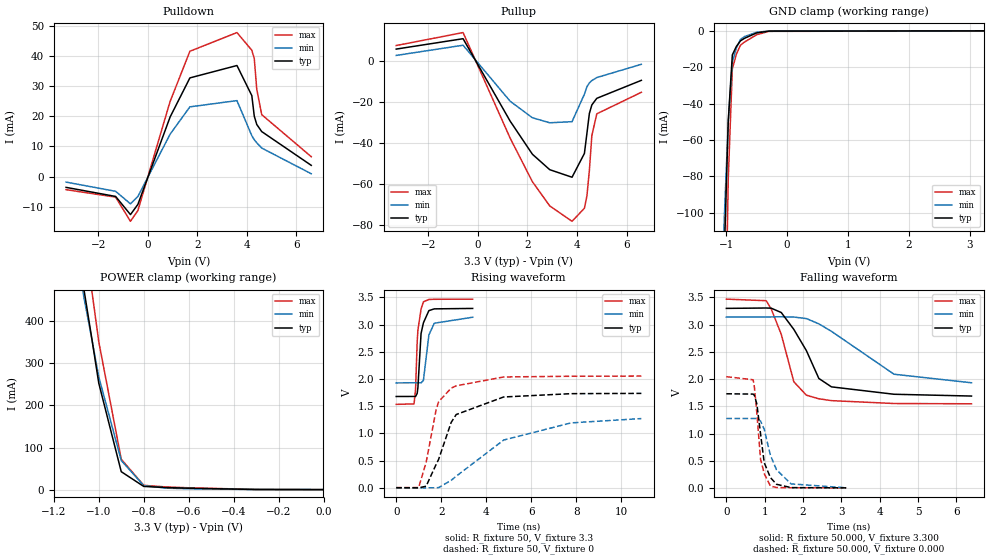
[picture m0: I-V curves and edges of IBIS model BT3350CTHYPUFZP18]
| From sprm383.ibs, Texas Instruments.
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|   Model Cell BT3350CTHYPUFZP18
[Model]   BT3350CTHYPUFZP18
Model_type   I/O
Polarity   Non-Inverting
Enable   Active-Low
Vinl =  0.8V
Vinh =  2V
Cref =  15.0000pF
Rref =  100.0000M
Vref =  0V
Vmeas =  1.65
C_comp   1.502503p   1.466075p   1.538374p
[Model Spec]
Vinl   0.8V   0.8V   0.8V
Vinh   2V   2V   2V
[Temperature Range]   25   105   0
[Voltage Range]   3.3   3.14   3.47
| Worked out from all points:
|   slope of the pulldown table from 0 to 0.495 V, typ, clamps not added: 44 ohm
|   slope of the pullup table from 0 to 0.495 V, typ, clamps not added: 42.8 ohm
|   GND clamp passes 1 mA (typ) near -0.48 V on its own axis
|   POWER clamp passes 1 mA (typ) near -0.41 V on its own axis
|   rising waveform, R_fixture 50, V_fixture 3.3: 20-80 % time 190ps typ, 246ps min, 155ps max; typ from 1.68 V to 3.3 V
|   rising waveform, R_fixture 50, V_fixture 0: 20-80 % time 1.09ns typ, 3.19ns min, 654ps max; typ from 0.003 V to 1.74 V
|   falling waveform, R_fixture 50.000, V_fixture 3.300: 20-80 % time 714ps typ, 1.44ns min, 481ps max; typ from 3.3 V to 1.69 V
|   falling waveform, R_fixture 50.000, V_fixture 0.000: 20-80 % time 214ps typ, 398ps min, 167ps max; typ from 1.73 V to 0.004 V
[POWER_clamp]
|   voltage   I(typ)   I(min)   I(max)
-3.3V     9.961A     8.611A     10.94A
-1.067V   478.9mA    459.3mA    610.8mA
-1.033V   365.9mA    363.6mA    481.1mA
-1V       253mA      268mA      351.4mA
-900mV    42.61mA    69.09mA    72.29mA
-800mV    7.588mA    9.637mA    10.15mA
-700mV    4.837mA    3.413mA    6.304mA
-600mV    3.264mA    2.054mA    4.281mA
-300mV    294.4uA    124uA      421.6uA
-11.55fV  111.7nA    122.5nA    531.5nA
[Pulldown]
|   voltage   I(typ)   I(min)   I(max)
-3.3V     -3.556mA   -1.81mA    -4.313mA
-1.3V     -6.559mA   -4.855mA   -6.788mA
-700mV    -12.57mA   -9.011mA   -14.79mA
-400mV    -9.189mA   -6.568mA   -11.22mA
900mV     19.73mA    14.05mA    24.87mA
1.7V      32.7mA     23.11mA    41.52mA
3.6V      36.8mA     25.18mA    47.71mA
4.2V      26.84mA    13.56mA    41.86mA
4.3V      20mA       12.22mA    39.07mA
4.4V      17.27mA    11.2mA     28.91mA
4.6V      14.92mA    9.466mA    20.53mA
6.6V      3.738mA    957.8uA    6.603mA
[Pullup]
|   voltage   I(typ)   I(min)   I(max)
-3.3V     6.065mA    2.956mA    7.802mA
-600mV    11.14mA    7.957mA    14.14mA
1.3V      -29.12mA   -19.41mA   -37.44mA
2.2V      -45.34mA   -27.51mA   -58.77mA
2.9V      -52.89mA   -29.96mA   -70.6mA
3.8V      -56.58mA   -29.42mA   -78.12mA
4.3V      -44.95mA   -15.98mA   -71.73mA
4.4V      -35.27mA   -12.36mA   -65.78mA
4.5V      -25.42mA   -10.48mA   -53.4mA
4.6V      -21.24mA   -9.347mA   -36.22mA
4.8V      -18mA      -7.852mA   -25.58mA
6.6V      -9.208mA   -1.37mA    -15.06mA
[GND_clamp]
|   voltage   I(typ)   I(min)   I(max)
-3.3V     -13.48A    -11.6A     -14.64A
-1.1V     -237.5mA   -179.6mA   -391mA
-1.033V   -124.2mA   -103.9mA   -204.6mA
-966.7mV  -49.5mA    -49.77mA   -81.23mA
-900mV    -13.27mA   -17.19mA   -20.98mA
-833.3mV  -8.566mA   -9.427mA   -12.84mA
-766.7mV  -5.513mA   -4.752mA   -7.902mA
-700mV    -4.108mA   -3.166mA   -6.147mA
-500mV    -1.143mA   -794.1uA   -2.132mA
-300mV    -166.2uA   -102.4uA   -290.4uA
3.233V    -8.734uA   9.395uA    -38.37uA
[Ramp]
| variable   typ   min   max
dV/dt_f   1.0019/0.7191069n  0.7872459/1.623878n   1.179669/0.4820844n
dV/dt_r   1.047343/1.100085n   0.7866504/3.393366n   1.235207/0.6500529n
R_load = 50
[Rising Waveform]
R_fixture = 50
V_fixture = 3.3
V_fixture_min = 3.14
V_fixture_max = 3.47
|   time   V(typ)   V(min)   V(max)
0s        1.68V      1.93V      1.535V
792ps     1.681V     1.931V     1.544V
860ps     1.681V     1.932V     1.813V
932ps     1.737V     1.931V     2.687V
964ps     1.844V     1.931V     2.9V
1.104ns   2.837V     1.931V     3.288V
1.208ns   3.034V     1.975V     3.421V
1.452ns   3.259V     2.812V     3.464V
1.692ns   3.291V     3.027V     3.467V
3.396ns   3.299V     3.137V     3.47V
[Rising Waveform]
R_fixture = 50
V_fixture = 0
V_fixture_min = 0
V_fixture_max = 0
|   time   V(typ)   V(min)   V(max)
0s        3.146mV    1.93mV     3.847mV
996ps     791.2uV    1.936mV    5.111mV
1.328ns   29.71mV    101.9uV    465.4mV
1.772ns   430.3mV    2.378mV    1.436V
1.884ns   524mV      4.058mV    1.584V
2.44ns    1.202V     138.2mV    1.833V
2.664ns   1.348V     213.8mV    1.876V
4.772ns   1.671V     879mV      2.039V
7.772ns   1.732V     1.195V     2.052V
10.89ns   1.737V     1.274V     2.055V
[Falling Waveform]
R_fixture = 50.000
V_fixture = 3.300
V_fixture_min = 3.140
V_fixture_max = 3.470
|  time   V(typ)   V(min)   V(max)
0s        3.3V       3.14V      3.47V
1.04ns    3.307V     3.143V     3.441V
1.172ns   3.303V     3.144V     3.286V
1.432ns   3.224V     3.145V     2.824V
1.76ns    2.914V     3.141V     1.952V
2.088ns   2.523V     3.113V     1.706V
2.412ns   2.013V     3.016V     1.64V
2.74ns    1.859V     2.879V     1.606V
4.372ns   1.723V     2.091V     1.553V
6.392ns   1.69V      1.934V     1.548V
[Falling Waveform]
R_fixture = 50.000
V_fixture = 0.000
V_fixture_min = 0.000
V_fixture_max = 0.000
|  time   V(typ)   V(min)   V(max)
0s        1.732V     1.278V     2.046V
700ps     1.726V     1.278V     1.989V
732ps     1.703V     1.279V     1.852V
796ps     1.544V     1.275V     1.377V
892ps     997.5mV    1.232V     530.4mV
988ps     467mV      1.079V     267.7mV
1.148ns   194.5mV    605.4mV    37.49mV
1.308ns   69.72mV    336.6mV    9.931mV
1.688ns   8.542mV    76.79mV    5.993mV
3.128ns   4.413mV    5.077mV    4.102mV
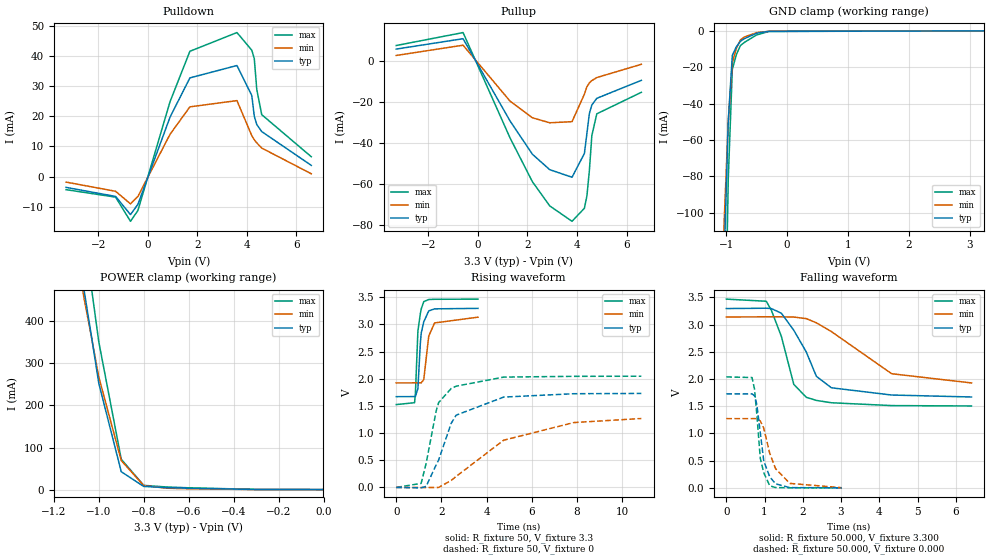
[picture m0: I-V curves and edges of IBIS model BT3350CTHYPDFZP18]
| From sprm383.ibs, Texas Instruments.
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|   Model Cell BT3350CTHYPDFZP18
[Model]   BT3350CTHYPDFZP18
Model_type   I/O
Polarity   Non-Inverting
Enable   Active-Low
Vinl =  0.8V
Vinh =  2V
Cref =  15.0000pF
Rref =  100.0000M
Vref =  0V
Vmeas =  1.65
C_comp   1.508835p   1.472578p   1.545342p
[Model Spec]
Vinl   0.8V   0.8V   0.8V
Vinh   2V   2V   2V
[Temperature Range]   25   105   0
[Voltage Range]   3.3   3.14   3.47
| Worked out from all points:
|   slope of the pulldown table from 0 to 0.495 V, typ, clamps not added: 44 ohm
|   slope of the pullup table from 0 to 0.495 V, typ, clamps not added: 42.8 ohm
|   GND clamp passes 1 mA (typ) near -0.49 V on its own axis
|   POWER clamp passes 1 mA (typ) near -0.40 V on its own axis
|   rising waveform, R_fixture 50, V_fixture 3.3: 20-80 % time 190ps typ, 246ps min, 157ps max; typ from 1.67 V to 3.3 V
|   rising waveform, R_fixture 50, V_fixture 0: 20-80 % time 1.09ns typ, 3.19ns min, 655ps max; typ from 0 V to 1.73 V
|   falling waveform, R_fixture 50.000, V_fixture 3.300: 20-80 % time 715ps typ, 1.44ns min, 479ps max; typ from 3.29 V to 1.67 V
|   falling waveform, R_fixture 50.000, V_fixture 0.000: 20-80 % time 213ps typ, 396ps min, 166ps max; typ from 1.73 V to 0.001 V
[POWER_clamp]
|   voltage   I(typ)   I(min)   I(max)
-3.3V     9.96A      8.611A     10.94A
-1.067V   478.9mA    459.2mA    610.8mA
-1.033V   365.9mA    363.6mA    481.1mA
-1V       253mA      268mA      351.4mA
-900mV    42.61mA    69.08mA    72.31mA
-800mV    7.612mA    9.647mA    10.2mA
-700mV    4.877mA    3.434mA    6.369mA
-600mV    3.319mA    2.085mA    4.366mA
-300mV    394.6uA    184.3uA    564.2uA
-11.55fV  142.7uA    86.75uA    197.1uA
[Pulldown]
|   voltage   I(typ)   I(min)   I(max)
-3.3V     -3.556mA   -1.81mA    -4.313mA
-1.3V     -6.558mA   -4.855mA   -6.788mA
-700mV    -12.57mA   -9.011mA   -14.79mA
-400mV    -9.189mA   -6.568mA   -11.22mA
900mV     19.74mA    14.05mA    24.87mA
1.7V      32.7mA     23.11mA    41.52mA
3.6V      36.8mA     25.18mA    47.71mA
4.2V      26.85mA    13.56mA    41.86mA
4.3V      20mA       12.22mA    39.07mA
4.4V      17.27mA    11.2mA     28.91mA
4.6V      14.92mA    9.466mA    20.53mA
6.6V      3.738mA    957.8uA    6.603mA
[Pullup]
|   voltage   I(typ)   I(min)   I(max)
-3.3V     6.065mA    2.955mA    7.802mA
-600mV    11.14mA    7.957mA    14.14mA
1.3V      -29.12mA   -19.41mA   -37.44mA
2.2V      -45.34mA   -27.51mA   -58.77mA
2.9V      -52.89mA   -29.96mA   -70.6mA
3.8V      -56.58mA   -29.42mA   -78.12mA
4.3V      -44.94mA   -15.98mA   -71.73mA
4.4V      -35.27mA   -12.36mA   -65.78mA
4.5V      -25.42mA   -10.48mA   -53.4mA
4.6V      -21.24mA   -9.347mA   -36.22mA
4.8V      -18mA      -7.852mA   -25.58mA
6.6V      -9.208mA   -1.37mA    -15.06mA
[GND_clamp]
|   voltage   I(typ)   I(min)   I(max)
-3.3V     -13.48A    -11.6A     -14.64A
-1.1V     -237.6mA   -179.7mA   -391.1mA
-1.033V   -124.3mA   -104mA     -204.6mA
-966.7mV  -49.55mA   -49.84mA   -81.29mA
-900mV    -13.32mA   -17.24mA   -21.02mA
-833.3mV  -8.603mA   -9.47mA    -12.87mA
-766.7mV  -5.537mA   -4.785mA   -7.915mA
-700mV    -4.118mA   -3.189mA   -6.143mA
-500mV    -1.111mA   -790.4uA   -2.074mA
-300mV    -91.74uA   -71.4uA    -180uA
3.233V    142.6uA    88.12uA    196.8uA
[Ramp]
| variable   typ   min   max
dV/dt_f   1.003801/0.7179774n  0.7885552/1.618059n   1.182195/0.4805983n
dV/dt_r   1.046072/1.105976n   0.785264/3.40284n   1.233956/0.6529987n
R_load = 50
[Rising Waveform]
R_fixture = 50
V_fixture = 3.3
V_fixture_min = 3.14
V_fixture_max = 3.47
|   time   V(typ)   V(min)   V(max)
0s        1.671V     1.924V     1.525V
812ps     1.672V     1.925V     1.56V
848ps     1.672V     1.925V     1.711V
960ps     1.819V     1.925V     2.878V
1.068ns   2.655V     1.925V     3.199V
1.108ns   2.843V     1.925V     3.286V
1.22ns    3.048V     1.987V     3.42V
1.44ns    3.249V     2.787V     3.459V
1.7ns     3.287V     3.028V     3.463V
3.62ns    3.296V     3.134V     3.466V
[Rising Waveform]
R_fixture = 50
V_fixture = 0
V_fixture_min = 0
V_fixture_max = 0
|   time   V(typ)   V(min)   V(max)
0s        47.1uV     22.63uV    79.1uV
1.104ns   -7.673mV   -136.5uV   74.88mV
1.324ns   19.79mV    -1.892mV   440.9mV
1.768ns   414.1mV    -1.08mV    1.408V
1.88ns    507.2mV    495.8uV    1.563V
2.432ns   1.179V     128.3mV    1.821V
2.652ns   1.33V      203.1mV    1.864V
4.756ns   1.663V     869.8mV    2.031V
7.856ns   1.725V     1.194V     2.045V
10.85ns   1.73V      1.269V     2.047V
[Falling Waveform]
R_fixture = 50.000
V_fixture = 3.300
V_fixture_min = 3.140
V_fixture_max = 3.470
|  time   V(typ)   V(min)   V(max)
0s        3.293V     3.138V     3.466V
1.044ns   3.299V     3.141V     3.427V
1.176ns   3.293V     3.142V     3.265V
1.44ns    3.207V     3.141V     2.78V
1.764ns   2.895V     3.137V     1.901V
2.092ns   2.494V     3.108V     1.663V
2.356ns   2.048V     3.031V     1.606V
2.748ns   1.838V     2.87V      1.563V
4.324ns   1.705V     2.096V     1.511V
6.412ns   1.669V     1.927V     1.504V
[Falling Waveform]
R_fixture = 50.000
V_fixture = 0.000
V_fixture_min = 0.000
V_fixture_max = 0.000
|  time   V(typ)   V(min)   V(max)
0s        1.725V     1.272V     2.038V
672ps     1.725V     1.272V     2.026V
736ps     1.692V     1.273V     1.818V
796ps     1.537V     1.269V     1.365V
888ps     1.014V     1.229V     542mV
980ps     490.5mV    1.093V     276.1mV
1.136ns   201.5mV    633.4mV    37.9mV
1.288ns   73.74mV    352mV      5.886mV
1.66ns    5.031mV    82.12mV    1.896mV
3.02ns    1.192mV    3.17mV     242uV
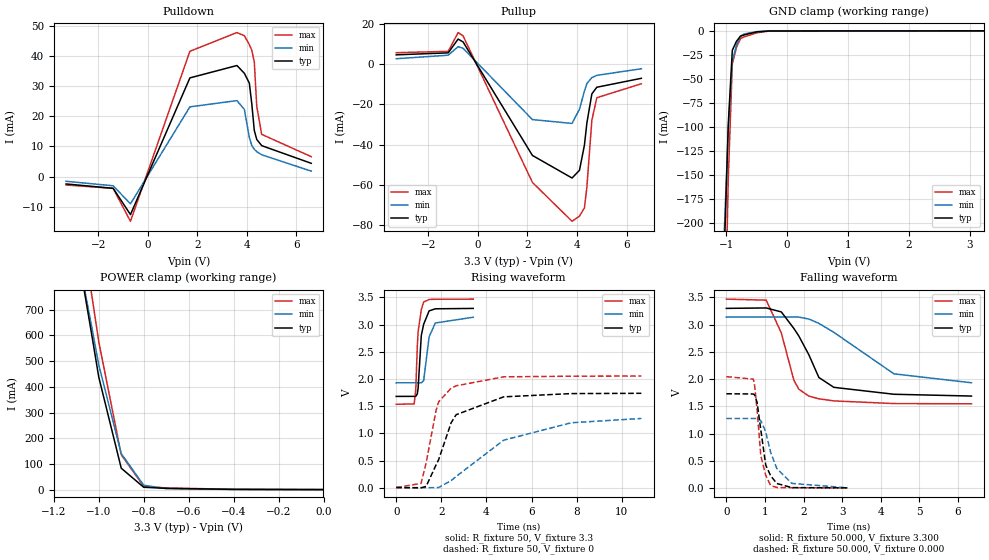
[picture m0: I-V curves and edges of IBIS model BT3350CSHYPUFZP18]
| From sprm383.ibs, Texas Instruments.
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|   Model Cell BT3350CSHYPUFZP18
[Model]   BT3350CSHYPUFZP18
Model_type   I/O
Polarity   Non-Inverting
Enable   Active-Low
Vinl =  0.8V
Vinh =  2V
Cref =  15.0000pF
Rref =  100.0000M
Vref =  0V
Vmeas =  1.65
C_comp   1.729411p   1.683527p   1.771376p
[Model Spec]
Vinl   0.8V   0.8V   0.8V
Vinh   2V   2V   2V
[Temperature Range]   25   105   0
[Voltage Range]   3.3   3.14   3.47
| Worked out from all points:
|   slope of the pulldown table from 0 to 0.495 V, typ, clamps not added: 44 ohm
|   slope of the pullup table from 0 to 0.495 V, typ, clamps not added: 42.8 ohm
|   GND clamp passes 1 mA (typ) near -0.48 V on its own axis
|   POWER clamp passes 1 mA (typ) near -0.41 V on its own axis
|   rising waveform, R_fixture 50, V_fixture 3.3: 20-80 % time 200ps typ, 262ps min, 161ps max; typ from 1.68 V to 3.3 V
|   rising waveform, R_fixture 50, V_fixture 0: 20-80 % time 1.08ns typ, 3.18ns min, 648ps max; typ from 0.003 V to 1.74 V
|   falling waveform, R_fixture 50.000, V_fixture 3.300: 20-80 % time 713ps typ, 1.43ns min, 481ps max; typ from 3.3 V to 1.69 V
|   falling waveform, R_fixture 50.000, V_fixture 0.000: 20-80 % time 225ps typ, 409ps min, 176ps max; typ from 1.73 V to 0.004 V
[POWER_clamp]
|   voltage   I(typ)   I(min)   I(max)
-3.3V     15.06A     13.76A     16A
-1.067V   785.8mA    796.7mA    959.4mA
-1.033V   611.7mA    640.9mA    767.4mA
-1V       437.6mA    485.2mA    575.3mA
-900mV    83.18mA    139.9mA    135.6mA
-800mV    9.15mA     17.08mA    12.66mA
-700mV    4.874mA    3.821mA    6.346mA
-400mV    906.7uA    477.6uA    1.218mA
-11.55fV  111.7nA    122.5nA    531.5nA
[Pulldown]
|   voltage   I(typ)   I(min)   I(max)
-3.3V     -2.42mA    -1.536mA   -2.768mA
-1.4V     -3.865mA   -3.029mA   -3.892mA
-700mV    -12.57mA   -9.01mA    -14.79mA
1.7V      32.7mA     23.11mA    41.52mA
3.6V      36.8mA     25.18mA    47.71mA
3.9V      34.21mA    22.24mA    46.65mA
4.1V      30.98mA    12.94mA    43.72mA
4.2V      24.06mA    10.3mA     41.84mA
4.3V      15.3mA     9.054mA    37.97mA
4.4V      12.31mA    8.283mA    23.22mA
4.6V      10.26mA    7.233mA    13.99mA
6.6V      4.412mA    1.834mA    6.626mA
[Pullup]
|   voltage   I(typ)   I(min)   I(max)
-3.3V     4.71mA     2.781mA    5.78mA
-1.2V     5.694mA    4.518mA    6.444mA
-800mV    12.56mA    8.755mA    15.79mA
-600mV    11.14mA    7.956mA    14.14mA
2.2V      -45.34mA   -27.51mA   -58.77mA
3.8V      -56.58mA   -29.42mA   -78.12mA
4.1V      -52.77mA   -22.36mA   -75.56mA
4.3V      -40.26mA   -13.34mA   -71.48mA
4.4V      -29.2mA    -9.578mA   -61.01mA
4.6V      -14.75mA   -6.625mA   -27.92mA
4.8V      -11.42mA   -5.502mA   -16.63mA
6.6V      -6.965mA   -2.214mA   -9.682mA
[GND_clamp]
|   voltage   I(typ)   I(min)   I(max)
-3.3V     -17.3A     -15.81A    -18.25A
-1.033V   -232.2mA   -209.7mA   -349.9mA
-966.7mV  -97.18mA   -102.7mA   -153.5mA
-900mV    -20.22mA   -31.77mA   -34.2mA
-833.3mV  -11mA      -14.95mA   -17.44mA
-766.7mV  -5.636mA   -5.437mA   -8.094mA
-700mV    -4.112mA   -3.216mA   -6.152mA
-500mV    -1.143mA   -794.3uA   -2.132mA
-300mV    -166.2uA   -102.4uA   -290.4uA
3.233V    -8.734uA   9.395uA    -38.37uA
[Ramp]
| variable   typ   min   max
dV/dt_f   1.001695/0.7159292n  0.7872142/1.616947n   1.179413/0.4810026n
dV/dt_r   1.04705/1.096909n   0.7864588/3.38681n   1.234969/0.6440918n
R_load = 50
[Rising Waveform]
R_fixture = 50
V_fixture = 3.3
V_fixture_min = 3.14
V_fixture_max = 3.47
|   time   V(typ)   V(min)   V(max)
0s        1.68V      1.93V      1.535V
796ps     1.681V     1.931V     1.542V
868ps     1.681V     1.931V     1.81V
936ps     1.727V     1.931V     2.605V
972ps     1.833V     1.931V     2.872V
1.112ns   2.799V     1.931V     3.275V
1.216ns   3.006V     1.97V      3.416V
1.46ns    3.254V     2.778V     3.464V
1.736ns   3.292V     3.031V     3.468V
3.416ns   3.299V     3.137V     3.47V
[Rising Waveform]
R_fixture = 50
V_fixture = 0
V_fixture_min = 0
V_fixture_max = 0
|   time   V(typ)   V(min)   V(max)
0s        3.146mV    1.93mV     3.847mV
1.104ns   -2.651mV   1.865mV    79.58mV
1.328ns   25.43mV    325.6uV    458.2mV
1.772ns   424.3mV    1.967mV    1.431V
1.88ns    514.8mV    3.472mV    1.58V
2.436ns   1.195V     131.1mV    1.832V
2.656ns   1.343V     206.5mV    1.875V
4.764ns   1.672V     874.6mV    2.04V
7.756ns   1.732V     1.195V     2.052V
10.87ns   1.737V     1.274V     2.055V
[Falling Waveform]
R_fixture = 50.000
V_fixture = 3.300
V_fixture_min = 3.140
V_fixture_max = 3.470
|  time   V(typ)   V(min)   V(max)
0s        3.3V       3.14V      3.47V
1.032ns   3.308V     3.143V     3.451V
1.424ns   3.235V     3.144V     2.849V
1.748ns   2.932V     3.142V     1.982V
1.876ns   2.794V     3.14V      1.817V
2.136ns   2.449V     3.104V     1.689V
2.396ns   2.031V     3.025V     1.64V
2.784ns   1.85V      2.86V      1.601V
4.34ns    1.723V     2.098V     1.552V
6.348ns   1.69V      1.934V     1.548V
[Falling Waveform]
R_fixture = 50.000
V_fixture = 0.000
V_fixture_min = 0.000
V_fixture_max = 0.000
|  time   V(typ)   V(min)   V(max)
0s        1.732V     1.278V     2.046V
700ps     1.728V     1.278V     2.001V
732ps     1.71V      1.278V     1.886V
796ps     1.577V     1.276V     1.442V
892ps     1.071V     1.241V     598.8mV
1.02ns    423.2mV    1.031V     235.5mV
1.148ns   225.4mV    654.8mV    47.46mV
1.308ns   84.09mV    359.6mV    10.27mV
1.696ns   8.561mV    86.11mV    5.947mV
3.136ns   4.391mV    5.082mV    4.064mV
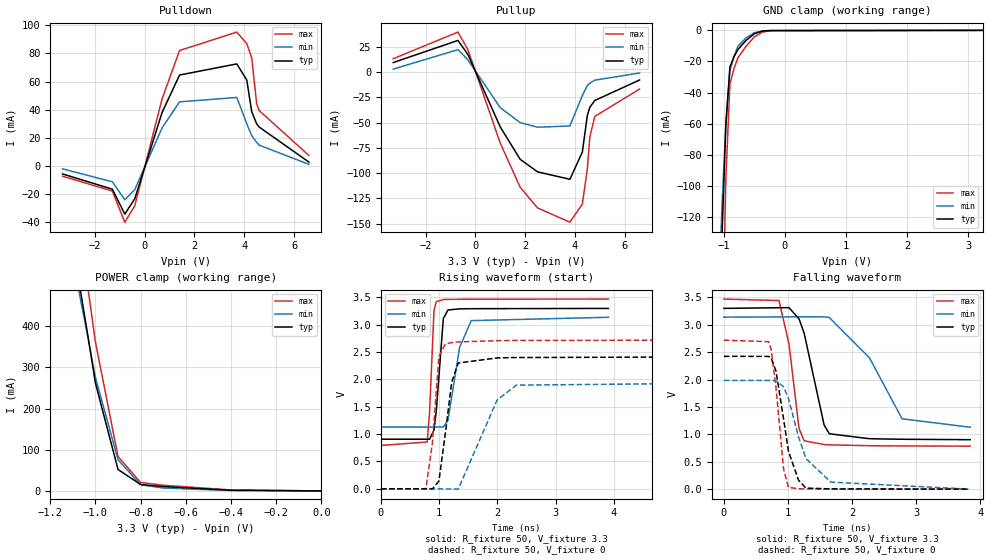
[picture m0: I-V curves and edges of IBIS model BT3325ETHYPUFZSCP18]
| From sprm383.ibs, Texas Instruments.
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|   Model Cell BT3325ETHYPUFZSCP18
[Model]   BT3325ETHYPUFZSCP18
Model_type   I/O
Polarity   Non-Inverting
Enable   Active-Low
Vinl =  0.8V
Vinh =  2V
Cref =  15.0000pF
Rref =  100.0000M
Vref =  0V
Vmeas =  1.65
C_comp   2.318211p   2.259633p   2.362549p
[Model Spec]
Vinl   0.8V   0.8V   0.8V
Vinh   2V   2V   2V
[Temperature Range]   25   105   0
[Voltage Range]   3.3   3.14   3.47
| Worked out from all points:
|   slope of the pulldown table from 0 to 0.495 V, typ, clamps not added: 17.8 ohm
|   slope of the pullup table from 0 to 0.495 V, typ, clamps not added: 17.6 ohm
|   GND clamp passes 1 mA (typ) near -0.42 V on its own axis
|   POWER clamp passes 1 mA (typ) near -0.34 V on its own axis
|   rising waveform, R_fixture 50, V_fixture 3.3: 20-80 % time 97.4ps typ, 203ps min, 66.3ps max; typ from 0.907 V to 3.3 V
|   rising waveform, R_fixture 50, V_fixture 0: 20-80 % time 175ps typ, 438ps min, 134ps max; typ from 0.002 V to 2.43 V
|   falling waveform, R_fixture 50, V_fixture 3.3: 20-80 % time 266ps typ, 582ps min, 179ps max; typ from 3.3 V to 0.905 V
|   falling waveform, R_fixture 50, V_fixture 0: 20-80 % time 218ps typ, 366ps min, 135ps max; typ from 2.42 V to 0.003 V
[POWER_clamp]
|   voltage   I(typ)   I(min)   I(max)
-3.3V     10A        8.651A     10.99A
-1.1V     600.9mA    563.1mA    751mA
-1.067V   487.9mA    467.1mA    621.2mA
-1.033V   374.8mA    371.2mA    491.4mA
-1V       261.8mA    275.2mA    361.5mA
-900mV    52.02mA    75.61mA    83.45mA
-800mV    15.6mA     14.93mA    20.49mA
-700mV    10.59mA    7.069mA    13.81mA
-400mV    1.748mA    903.5uA    2.354mA
-11.55fV  124.3nA    164.4nA    588nA
[Pulldown]
|   voltage   I(typ)   I(min)   I(max)
-3.3V     -5.588mA   -1.951mA   -7.186mA
-1.3V     -16.41mA   -11.18mA   -17.74mA
-800mV    -34.13mA   -23.92mA   -39.86mA
-400mV    -23.24mA   -16.71mA   -28.27mA
700mV     38.17mA    27.19mA    47.83mA
1.4V      64.68mA    45.63mA    82.09mA
3.7V      72.6mA     48.77mA    95.2mA
4.1V      61.2mA     30.17mA    87mA
4.3V      38.67mA    21.61mA    76.87mA
4.5V      29.97mA    16.82mA    44.22mA
4.6V      27.73mA    14.88mA    39.44mA
6.6V      2.818mA    1.22mA     7.531mA
[Pullup]
|   voltage   I(typ)   I(min)   I(max)
-3.3V     9.262mA    2.789mA    13.04mA
-700mV    31.1mA     21.99mA    39.36mA
-300mV    17.26mA    11.94mA    22.03mA
1V        -54.36mA   -35.32mA   -70.28mA
1.8V      -86.33mA   -50.13mA   -113.9mA
2.5V      -98.76mA   -54.63mA   -134.4mA
3.8V      -106.1mA   -53.41mA   -148.5mA
4.3V      -79.17mA   -23.24mA   -130.7mA
4.5V      -42.98mA   -13.33mA   -95.87mA
4.6V      -34.96mA   -11.11mA   -64.34mA
4.8V      -28.21mA   -8.159mA   -44mA
6.6V      -7.979mA   -1.067mA   -16.94mA
[GND_clamp]
|   voltage   I(typ)   I(min)   I(max)
-3.3V     -13.5A     -11.62A    -14.66A
-1.1V     -249.7mA   -192.9mA   -403.2mA
-1.033V   -136.4mA   -116.2mA   -218.5mA
-966.7mV  -61.06mA   -60.63mA   -95.68mA
-900mV    -23.53mA   -26.24mA   -34.7mA
-833.3mV  -17.01mA   -16.58mA   -24.53mA
-766.7mV  -12.16mA   -10.14mA   -17.47mA
-633.3mV  -6.418mA   -4.769mA   -10.13mA
-500mV    -2.163mA   -1.522mA   -4.22mA
-366.7mV  -453.2uA   -326.9uA   -1.067mA
-233.3mV  -159.3uA   -95.62uA   -261.4uA
3.233V    -8.746uA   10.5uA     -38.4uA
[Ramp]
| variable   typ   min   max
dV/dt_f   1.451059/0.2690875n   1.234827/0.5942056n   1.620616/0.1779413n
dV/dt_r   1.462941/0.1740186n   1.204351/0.4409547n   1.637995/0.1078293n
R_load = 50
[Rising Waveform]
R_fixture = 50
V_fixture = 3.3
V_fixture_min = 3.14
V_fixture_max = 3.47
|   time   V(typ)   V(min)   V(max)
0s        907.1mV    1.129V     792.9mV
796ps     907.3mV    1.129V     857mV
836ps     907.4mV    1.13V      1.405V
912ps     1.075V     1.129V     3.259V
952ps     1.434V     1.129V     3.423V
1.072ns   3.113V     1.133V     3.461V
1.152ns   3.27V      1.253V     3.464V
1.352ns   3.291V     2.588V     3.466V
1.552ns   3.294V     3.076V     3.468V
3.908ns   3.299V     3.137V     3.47V
[Rising Waveform]
R_fixture = 50
V_fixture = 0
V_fixture_min = 0
V_fixture_max = 0
|   time   V(typ)   V(min)   V(max)
0s        1.739mV    1.151mV    2.041mV
772ps     1.619mV    1.151mV    -188.5uV
884ps     -2.44mV    1.161mV    835mV
996ps     142.1mV    1.1mV      2.421V
1.108ns   1.024V     -1.769mV   2.649V
1.216ns   1.95V      -3.335mV   2.674V
1.328ns   2.3V       -5.939mV   2.686V
1.996ns   2.394V     1.624V     2.709V
2.328ns   2.401V     1.896V     2.713V
10.88ns   2.428V     1.982V     2.728V
[Falling Waveform]
R_fixture = 50
V_fixture = 3.3
V_fixture_min = 3.14
V_fixture_max = 3.47
|   time   V(typ)   V(min)   V(max)
0s        3.3V       3.14V      3.47V
860ps     3.312V     3.144V     3.443V
1.016ns   3.313V     3.145V     2.653V
1.172ns   3.109V     3.147V     1.112V
1.252ns   2.849V     3.148V     884.8mV
1.564ns   1.173V     3.146V     816.4mV
1.644ns   1.013V     3.134V     810.9mV
2.272ns   922.2mV    2.397V     794.6mV
2.78ns    912.4mV    1.286V     790.2mV
3.844ns   904.7mV    1.132V     786.9mV
[Falling Waveform]
R_fixture = 50
V_fixture = 0
V_fixture_min = 0
V_fixture_max = 0
|   time   V(typ)   V(min)   V(max)
0s        2.425V     1.986V     2.72V
696ps     2.424V     1.986V     2.693V
736ps     2.399V     1.987V     2.56V
812ps     2.162V     1.98V      1.871V
932ps     1.279V     1.869V     367.1mV
1.008ns   693.3mV    1.656V     35.02mV
1.164ns   167mV      960.8mV    9.461mV
1.28ns    21.47mV    561mV      7.233mV
1.668ns   7.525mV    130.6mV    4.21mV
3.816ns   2.81mV     4.299mV    2.111mV
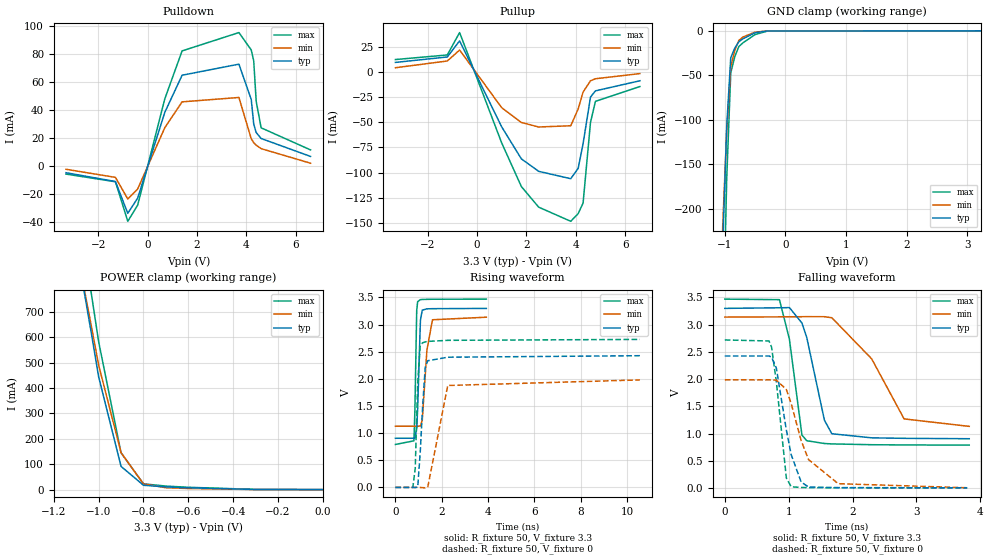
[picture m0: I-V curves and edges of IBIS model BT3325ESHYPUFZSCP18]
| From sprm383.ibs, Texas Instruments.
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|   Model Cell BT3325ESHYPUFZSCP18
[Model]   BT3325ESHYPUFZSCP18
Model_type   I/O
Polarity   Non-Inverting
Enable   Active-Low
Vinl =  0.8V
Vinh =  2V
Cref =  15.0000pF
Rref =  100.0000M
Vref =  0V
Vmeas =  1.65
C_comp   2.566034p   2.48891p   2.624395p
[Model Spec]
Vinl   0.8V   0.8V   0.8V
Vinh   2V   2V   2V
[Temperature Range]   25   105   0
[Voltage Range]   3.3   3.14   3.47
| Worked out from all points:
|   slope of the pulldown table from 0 to 0.495 V, typ, clamps not added: 17.8 ohm
|   slope of the pullup table from 0 to 0.495 V, typ, clamps not added: 17.6 ohm
|   GND clamp passes 1 mA (typ) near -0.42 V on its own axis
|   POWER clamp passes 1 mA (typ) near -0.34 V on its own axis
|   rising waveform, R_fixture 50, V_fixture 3.3: 20-80 % time 102ps typ, 216ps min, 68.9ps max; typ from 0.907 V to 3.3 V
|   rising waveform, R_fixture 50, V_fixture 0: 20-80 % time 201ps typ, 442ps min, 134ps max; typ from 0.002 V to 2.43 V
|   falling waveform, R_fixture 50, V_fixture 3.3: 20-80 % time 270ps typ, 580ps min, 180ps max; typ from 3.3 V to 0.905 V
|   falling waveform, R_fixture 50, V_fixture 0: 20-80 % time 226ps typ, 377ps min, 137ps max; typ from 2.42 V to 0.003 V
[POWER_clamp]
|   voltage   I(typ)   I(min)   I(max)
-3.3V     15.08A     13.77A     16.02A
-1.067V   791.8mA    802mA      966mA
-1.033V   617.9mA    646.2mA    774.2mA
-1V       444mA      490.4mA    582.3mA
-900mV    91.5mA     145.4mA    144.9mA
-800mV    17.11mA    22.25mA    22.89mA
-700mV    10.63mA    7.472mA    13.85mA
-600mV    6.978mA    4.341mA    9.164mA
-300mV    517.2uA    207.4uA    747uA
-11.55fV  124.3nA    164.4nA    588nA
[Pulldown]
|   voltage   I(typ)   I(min)   I(max)
-3.3V     -5.059mA   -2.603mA   -6.052mA
-1.3V     -11.37mA   -8.396mA   -11.53mA
-800mV    -34.11mA   -23.85mA   -39.82mA
-400mV    -23.24mA   -16.71mA   -28.27mA
700mV     38.17mA    27.19mA    47.83mA
1.4V      64.68mA    45.63mA    82.09mA
3.7V      72.6mA     48.77mA    95.2mA
4.2V      47.31mA    19.2mA     82.76mA
4.3V      29.74mA    16.47mA    74.92mA
4.4V      23.68mA    14.69mA    45.98mA
4.6V      19.42mA    12.16mA    27.05mA
6.6V      6.582mA    1.736mA    11.26mA
[Pullup]
|   voltage   I(typ)   I(min)   I(max)
-3.3V     9.651mA    4.35mA     12.5mA
-1.2V     15.05mA    11.05mA    17.06mA
-700mV    31.1mA     21.96mA    39.35mA
1V        -54.36mA   -35.32mA   -70.28mA
1.8V      -86.33mA   -50.13mA   -113.9mA
2.5V      -98.76mA   -54.63mA   -134.4mA
3.8V      -106.1mA   -53.41mA   -148.5mA
4.1V      -95.85mA   -36.78mA   -140.9mA
4.3V      -71.22mA   -19.86mA   -130.3mA
4.6V      -24.85mA   -8.628mA   -50.06mA
4.8V      -18.68mA   -6.618mA   -29.08mA
6.6V      -8.615mA   -1.481mA   -14.36mA
[GND_clamp]
|   voltage   I(typ)   I(min)   I(max)
-3.3V     -17.31A    -15.82A    -18.25A
-1.033V   -242.5mA   -220.3mA   -361.2mA
-966.7mV  -107.7mA   -112.6mA   -166.1mA
-900mV    -30.23mA   -40.48mA   -47.3mA
-833.3mV  -19.36mA   -21.98mA   -28.91mA
-766.7mV  -12.28mA   -10.81mA   -17.65mA
-700mV    -9.011mA   -6.973mA   -13.53mA
-500mV    -2.163mA   -1.523mA   -4.22mA
-300mV    -188.2uA   -126.3uA   -366.9uA
3.233V    -8.746uA   10.5uA     -38.4uA
[Ramp]
| variable   typ   min   max
dV/dt_f   1.45081/0.2712729n   1.234587/0.5921923n   1.620388/0.1799517n
dV/dt_r   1.462661/0.1782883n   1.20429/0.4441313n   1.63791/0.1110365n
R_load = 50
[Rising Waveform]
R_fixture = 50
V_fixture = 3.3
V_fixture_min = 3.14
V_fixture_max = 3.47
|   time   V(typ)   V(min)   V(max)
0s        907.1mV    1.129V     792.9mV
800ps     907.3mV    1.129V     859.8mV
840ps     907.4mV    1.129V     1.396V
920ps     1.089V     1.129V     3.263V
960ps     1.44V      1.129V     3.423V
1.08ns    3.081V     1.132V     3.461V
1.16ns    3.267V     1.242V     3.464V
1.36ns    3.291V     2.528V     3.466V
1.6ns     3.294V     3.09V      3.468V
3.928ns   3.299V     3.137V     3.47V
[Rising Waveform]
R_fixture = 50
V_fixture = 0
V_fixture_min = 0
V_fixture_max = 0
|   time   V(typ)   V(min)   V(max)
0s        1.739mV    1.151mV    2.041mV
752ps     1.717mV    1.154mV    1.508mV
856ps     -796.4uV   1.154mV    350.3mV
964ps     9.605mV    1.154mV    1.933V
1.072ns   649mV      273.5uV    2.623V
1.18ns    1.519V     -2.383mV   2.667V
1.288ns   2.214V     -6.646mV   2.682V
1.396ns   2.335V     2.576mV    2.691V
2.26ns    2.4V       1.879V     2.711V
10.56ns   2.428V     1.982V     2.728V
[Falling Waveform]
R_fixture = 50
V_fixture = 3.3
V_fixture_min = 3.14
V_fixture_max = 3.47
|   time   V(typ)   V(min)   V(max)
0s        3.3V       3.14V      3.47V
856ps     3.311V     3.144V     3.46V
1.012ns   3.314V     3.145V     2.734V
1.208ns   3.031V     3.147V     972.8mV
1.284ns   2.763V     3.148V     867.8mV
1.56ns    1.246V     3.147V     817.1mV
1.676ns   996.5mV    3.128V     809.6mV
2.3ns     921.3mV    2.373V     794.9mV
2.808ns   912.1mV    1.269V     790.7mV
3.828ns   904.9mV    1.132V     787.5mV
[Falling Waveform]
R_fixture = 50
V_fixture = 0
V_fixture_min = 0
V_fixture_max = 0
|   time   V(typ)   V(min)   V(max)
0s        2.425V     1.986V     2.72V
692ps     2.425V     1.986V     2.701V
732ps     2.405V     1.986V     2.591V
808ps     2.199V     1.982V     1.948V
964ps     1.067V     1.808V     183.4mV
1.04ns    611.7mV    1.549V     22.08mV
1.196ns   109.2mV    869.3mV    8.644mV
1.312ns   17.39mV    521.4mV    6.783mV
1.776ns   6.724mV    78.47mV    3.718mV
3.796ns   2.783mV    4.296mV    2.07mV
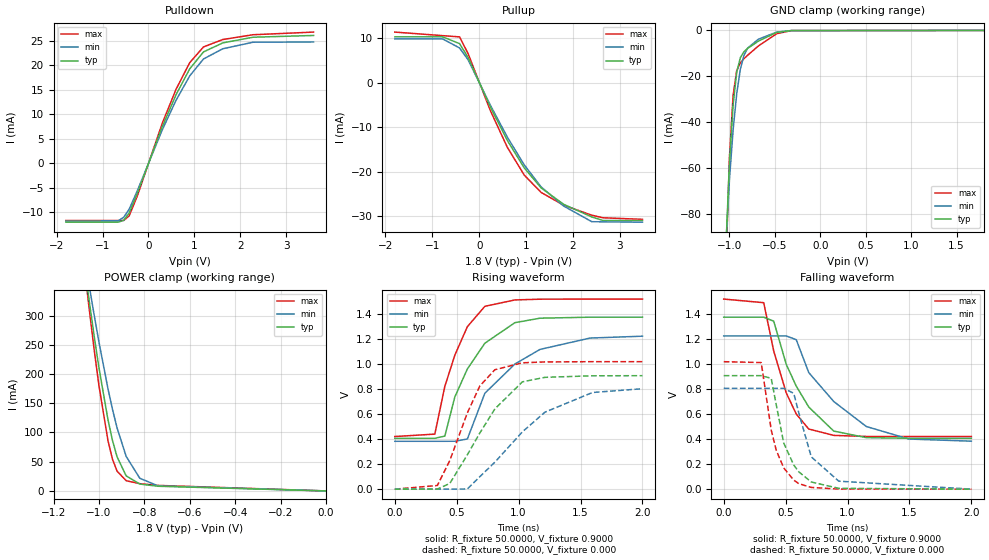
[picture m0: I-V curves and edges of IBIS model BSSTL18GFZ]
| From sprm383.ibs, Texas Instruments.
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|   Model Cell BSSTL18GFZ
[Model]   BSSTL18GFZ
Model_type   I/O
Polarity   Non-Inverting
Enable   Active-Low
Vinl =   0.6500V
Vinh =   1.1500V
Vmeas =   0.9000V
Cref =   5.0000pF
Rref =  50.0000
Vref =   0.9000V
C_comp   1.4120pF   1.3580pF   1.4210pF
[Temperature Range]   25.0000   0.1250k   -40.0000
[Voltage Range]   1.8000V   1.6200V   1.9500V
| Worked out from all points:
|   slope of the pulldown table from 0 to 0.27 V, typ, clamps not added: 40.2 ohm
|   slope of the pullup table from 0 to 0.27 V, typ, clamps not added: 43.4 ohm
|   GND clamp passes 1 mA (typ) near -0.49 V on its own axis
|   POWER clamp passes 1 mA (typ) near -0.39 V on its own axis
|   rising waveform, R_fixture 50.0000, V_fixture 0.9000: 20-80 % time 289ps typ, 420ps min, 224ps max; typ from 0.406 V to 1.38 V
|   rising waveform, R_fixture 50.0000, V_fixture 0.000: 20-80 % time 365ps typ, 550ps min, 248ps max; typ from 0 V to 0.908 V
|   falling waveform, R_fixture 50.0000, V_fixture 0.9000: 20-80 % time 280ps typ, 433ps min, 205ps max; typ from 1.38 V to 0.407 V
|   falling waveform, R_fixture 50.0000, V_fixture 0.000: 20-80 % time 157ps typ, 187ps min, 132ps max; typ from 0.908 V to 0 V
[Pulldown]
| voltage   I(typ)   I(min)   I(max)
-1.8V     -12.08mA   -11.88mA   -11.73mA
-660mV    -12.08mA   -11.81mA   NA
-540mV    -11.7mA    -11.08mA   -11.73mA
-420mV    -10.19mA   -9.416mA   -10.78mA
-240mV    -6.102mA   -5.589mA   -6.644mA
300mV     7.418mA    6.767mA    8.094mA
600mV     13.94mA    12.8mA     15.05mA
900mV     19.26mA    17.82mA    20.52mA
1.2V      22.71mA    21.27mA    23.73mA
1.62V     24.55mA    23.35mA    25.24mA
2.28V     25.71mA    24.69mA    26.22mA
3.6V      26.07mA    24.74mA    26.76mA
[Pullup]
| voltage   I(typ)   I(min)   I(max)
-1.8V     10.26mA    9.794mA    11.33mA
-780mV    10.26mA    9.794mA    NA
-420mV    8.744mA    7.766mA    10.25mA
-240mV    5.67mA     5.15mA     6.551mA
240mV     -5.556mA   -5.145mA   -6.376mA
600mV     -13.02mA   -12.28mA   -14.57mA
960mV     -19.18mA   -18.51mA   -20.8mA
1.32V     -23.68mA   -23.46mA   -24.69mA
1.8V      -27.35mA   -27.75mA   -27.56mA
2.4V      -30.2mA    -31.26mA   -29.8mA
2.64V     -30.99mA   NA         -30.38mA
3.48V     -30.99mA   -31.37mA   -30.73mA
[GND_clamp]
| voltage   I(typ)   I(min)   I(max)
-1.8V     -3.609A    -2.849A    -4.281A
-1.04V    -95.02mA   -93.84mA   -103.7mA
-1V       -57.11mA   -64.77mA   -54.91mA
-960mV    -32.43mA   -43.25mA   -28.19mA
-920mV    -18.12mA   -27.4mA    -17.44mA
-880mV    -11.8mA    -16.8mA    -14.03mA
-840mV    -9.234mA   -10.78mA   -12.26mA
-800mV    -7.789mA   -7.669mA   -10.78mA
-680mV    -4.598mA   -3.775mA   -6.691mA
-480mV    -844.9uA   -711uA     -1.413mA
-320mV    -39.8uA    -55.83uA   -65.71uA
1.8V      20.78nA    61.17uA    1.65nA
[POWER_clamp]
| voltage   I(typ)   I(min)   I(max)
-1.8V     2.924A     2.487A     3.338A
-1.06V    374.5mA    392.1mA    369mA
-1.04V    317.2mA    344.6mA    302.1mA
-1.02V    262.4mA    298.7mA    238.7mA
-1V       210.8mA    254.8mA    180.3mA
-960mV    121.4mA    174.5mA    85.66mA
-940mV    85.9mA     139.1mA    53.94mA
-920mV    58.16mA    107.7mA    33.78mA
-880mV    25.76mA    59.06mA    17.52mA
-820mV    11.76mA    21.67mA    12.36mA
-740mV    7.995mA    8.741mA    9.45mA
0V        20.78nA    115.4nA    23.43nA
[Ramp]
| variable   typ   min   max
dV/dt_r   0.5447/0.3617n   0.4821/0.5648n   0.6119/0.2455n
dV/dt_f   0.5616/0.3154n   0.4886/0.5464n   0.6223/0.2265n
R_load = 50.0000
[Rising Waveform]
R_fixture = 50.0000
V_fixture = 0.9000
V_fixture_min = 0.8100
V_fixture_max = 0.9750
| time   V(typ)   V(min)   V(max)
0s        406.5mV    383.1mV    421.1mV
323.2ps   407.1mV    383.1mV    440.5mV
404ps     424.7mV    383.1mV    822.6mV
484.8ps   738.2mV    383.4mV    1.072V
585.9ps   961.7mV    401.4mV    1.3V
727.3ps   1.168V     767.8mV    1.463V
969.7ps   1.332V     1.001V     1.514V
1.172ns   1.368V     1.118V     1.52V
1.576ns   1.376V     1.209V     1.521V
2ns       1.376V     1.224V     1.521V
[Rising Waveform]
R_fixture = 50.0000
V_fixture = 0.000
V_fixture_min = 0.000
V_fixture_max = 0.000
| time   V(typ)   V(min)   V(max)
0s        46.71uV    67.9uV     47.16uV
343.4ps   722uV      70uV       29.44mV
444.4ps   46.25mV    168.3uV    230mV
585.9ps   275.1mV    1.483mV    610mV
686.9ps   449.7mV    100.2mV    826.4mV
808.1ps   642.1mV    216mV      955.5mV
1.03ns    858.7mV    458.5mV    1.011V
1.212ns   894.7mV    615.8mV    1.018V
1.596ns   907.1mV    773.5mV    1.02V
2ns       907.9mV    803.6mV    1.02V
[Falling Waveform]
R_fixture = 50.0000
V_fixture = 0.9000
V_fixture_min = 0.8100
V_fixture_max = 0.9750
| time   V(typ)   V(min)   V(max)
0s        1.376V     1.226V     1.521V
323.2ps   1.376V     1.226V     1.492V
404ps     1.344V     1.226V     1.105V
505.1ps   998.9mV    1.226V     770.2mV
585.9ps   823.9mV    1.196V     601.1mV
686.9ps   657mV      932.6mV    481.2mV
888.9ps   464.5mV    701.1mV    430.3mV
1.152ns   412.2mV    501.2mV    421.8mV
1.495ns   407.1mV    401.2mV    421.2mV
2ns       406.7mV    384mV      421.2mV
[Falling Waveform]
R_fixture = 50.0000
V_fixture = 0.000
V_fixture_min = 0.000
V_fixture_max = 0.000
| time   V(typ)   V(min)   V(max)
0s        908.2mV    806.7mV    1.02V
303ps     908.2mV    806.7mV    1.013V
383.8ps   887mV      806.7mV    473.3mV
424.2ps   676.1mV    806.7mV    311.6mV
484.8ps   368.8mV    806.8mV    170.2mV
565.7ps   193.2mV    766.8mV    71.95mV
606.1ps   139.3mV    611.8mV    44.47mV
707.1ps   57.39mV    258.4mV    13.9mV
929.3ps   6.76mV     63.88mV    1.028mV
2ns       167.9uV    258.3uV    66.47uV
